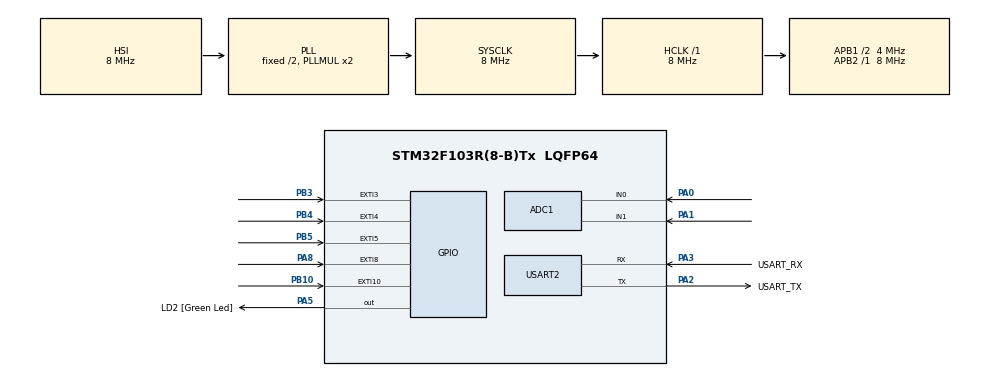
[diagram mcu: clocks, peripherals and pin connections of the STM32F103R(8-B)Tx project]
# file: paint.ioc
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ADC1.Channel-0\#ChannelRegularConversion=ADC_CHANNEL_0
ADC1.NbrOfConversionFlag=1
ADC1.Rank-0\#ChannelRegularConversion=1
ADC1.SamplingTime-0\#ChannelRegularConversion=ADC_SAMPLETIME_1CYCLE_5
ADC1.master=1
ADC2.Channel-0\#ChannelRegularConversion=ADC_CHANNEL_0
ADC2.NbrOfConversionFlag=1
ADC2.Rank-0\#ChannelRegularConversion=1
ADC2.SamplingTime-0\#ChannelRegularConversion=ADC_SAMPLETIME_1CYCLE_5
Mcu.Family=STM32F1
Mcu.Name=STM32F103R(8-B)Tx
Mcu.Package=LQFP64
NVIC.PriorityGroup=NVIC_PRIORITYGROUP_4
PA0-WKUP.Signal=SharedAnalog_PA0
PA1.Signal=SharedAnalog_PA1
PA13.GPIO_Label=TMS
PA13.Mode=Serial_Wire
PA13.Signal=SYS_JTMS-SWDIO
PA14.GPIO_Label=TCK
PA14.Mode=Serial_Wire
PA14.Signal=SYS_JTCK-SWCLK
PA2.GPIO_Label=USART_TX
PA2.GPIO_Mode=GPIO_MODE_AF_PP
PA2.GPIO_PuPd=GPIO_NOPULL
PA2.GPIO_Speed=GPIO_SPEED_FREQ_LOW
PA2.Mode=Asynchronous
PA2.Signal=USART2_TX
PA3.GPIO_Label=USART_RX
PA3.GPIO_Mode=GPIO_MODE_AF_PP
PA3.GPIO_PuPd=GPIO_NOPULL
PA3.GPIO_Speed=GPIO_SPEED_FREQ_LOW
PA3.Mode=Asynchronous
PA3.Signal=USART2_RX
PA5.GPIO_Label=LD2 [Green Led]
PA5.GPIO_ModeDefaultOutputPP=GPIO_MODE_OUTPUT_PP
PA5.GPIO_PuPd=GPIO_NOPULL
PA5.GPIO_Speed=GPIO_SPEED_FREQ_LOW
PA5.Signal=GPIO_Output
PA8.Signal=GPXTI8
PB10.Signal=GPXTI10
PB3.Signal=GPXTI3
PB4.Signal=GPXTI4
PB5.Signal=GPXTI5
PC14-OSC32_IN.Mode=LSE-External-Oscillator
PC14-OSC32_IN.Signal=RCC_OSC32_IN
PC15-OSC32_OUT.Mode=LSE-External-Oscillator
PC15-OSC32_OUT.Signal=RCC_OSC32_OUT
PD0-OSC_IN.Mode=HSE-External-Clock-Source
PD0-OSC_IN.Signal=RCC_OSC_IN
PD1-OSC_OUT.Mode=HSE-External-Clock-Source
PD1-OSC_OUT.Signal=RCC_OSC_OUT
ProjectManager.HeapSize=0x200
ProjectManager.StackSize=0x400
ProjectManager.TargetToolchain=MDK-ARM V5.32
RCC.AHBFreq_Value=8000000
RCC.APB1CLKDivider=RCC_HCLK_DIV2
RCC.APB1Freq_Value=4000000
RCC.APB1TimFreq_Value=8000000
RCC.APB2Freq_Value=8000000
RCC.APB2TimFreq_Value=8000000
RCC.HCLKFreq_Value=8000000
RCC.RTCClockSelection=RCC_RTCCLKSOURCE_LSE
RCC.SYSCLKFreq_VALUE=8000000
RCC.SYSCLKSource=RCC_SYSCLKSOURCE_PLLCLK
RCC.USBFreq_Value=8000000
SH.SharedAnalog_PA0.0=GPIO_Analog
SH.SharedAnalog_PA0.1=ADC1_IN0,IN0
SH.SharedAnalog_PA0.2=ADC2_IN0,IN0
SH.SharedAnalog_PA1.0=GPIO_Analog
SH.SharedAnalog_PA1.1=ADC1_IN1,IN1
SH.SharedAnalog_PA1.2=ADC2_IN1,IN1
USART2.VirtualMode=VM_ASYNC
board=NUCLEO-F103RB

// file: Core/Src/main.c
/* USER CODE BEGIN Header */
/**
  ******************************************************************************
  * @file           : main.c
  * @brief          : Main program body
  ******************************************************************************
  * @attention
  *
  * Copyright (c) 2025 STMicroelectronics.
  * All rights reserved.
  *
  * This software is licensed under terms that can be found in the LICENSE file
  * in the root directory of this software component.
  * If no LICENSE file comes with this software, it is provided AS-IS.
  *
  ******************************************************************************
  */
/* USER CODE END Header */
#include "main.h"

/* USER CODE BEGIN Includes */
#include <stdio.h>
#include <string.h>
/* USER CODE END Includes */

ADC_HandleTypeDef hadc1;
ADC_HandleTypeDef hadc2;

UART_HandleTypeDef huart2;

/* USER CODE BEGIN PV */
// Button state flags (set by interrupts, read in main loop)
volatile uint8_t buttonA_pressed = 0;
volatile uint8_t buttonB_pressed = 0;
volatile uint8_t buttonC_pressed = 0;
volatile uint8_t buttonD_pressed = 0;
volatile uint8_t buttonE_pressed = 0;
volatile uint8_t buttonF_pressed = 0;
volatile uint8_t joystickButton_pressed = 0;

/* USER CODE END PV */

void SystemClock_Config(void);
static void MX_GPIO_Init(void);
static void MX_USART2_UART_Init(void);
static void MX_ADC1_Init(void);
static void MX_ADC2_Init(void);
/* USER CODE BEGIN PFP */
uint16_t Read_ADC(ADC_HandleTypeDef* hadc);
void Send_UART_Data(uint16_t x, uint16_t y, uint8_t buttonE);
/* USER CODE END PFP */

int main(void)
{

  /* MCU Configuration--------------------------------------------------------*/

  /* Reset of all peripherals, Initializes the Flash interface and the Systick. */
  HAL_Init();

  /* Configure the system clock */
  SystemClock_Config();

  /* Initialize all configured peripherals */
  MX_GPIO_Init();
  MX_USART2_UART_Init();
  MX_ADC1_Init();
  MX_ADC2_Init();
  /* USER CODE BEGIN 2 */

  // Enable EXTI interrupts in NVIC
  // EXTI3 for PB3 (Button B)
  HAL_NVIC_SetPriority(EXTI3_IRQn, 0, 0);
  HAL_NVIC_EnableIRQ(EXTI3_IRQn);
  // EXTI4 for PB4 (Button C)
  HAL_NVIC_SetPriority(EXTI4_IRQn, 0, 0);
  HAL_NVIC_EnableIRQ(EXTI4_IRQn);
  // EXTI9_5 for PB5 (Button D), PA8 (Button F), PA9 (Joystick Button)
  HAL_NVIC_SetPriority(EXTI9_5_IRQn, 0, 0);
  HAL_NVIC_EnableIRQ(EXTI9_5_IRQn);
  // EXTI15_10 for PA10 (Button A), PB10 (Button E)
  HAL_NVIC_SetPriority(EXTI15_10_IRQn, 0, 0);
  HAL_NVIC_EnableIRQ(EXTI15_10_IRQn);

  /* USER CODE END 2 */

  /* Infinite loop */
  /* USER CODE BEGIN WHILE */
  uint32_t last_send_time = 0;

  while (1)
  {
    /* USER CODE END WHILE */

    /* USER CODE BEGIN 3 */
    // Read joystick position
    uint16_t joystick_x = Read_ADC(&hadc1);  // PA0 - X axis
    uint16_t joystick_y = Read_ADC(&hadc2);  // PA1 - Y axis

    // Send data via UART (every ~50ms to avoid flooding)
    uint32_t current_time = HAL_GetTick();
    if(current_time - last_send_time >= 50)
    {
      Send_UART_Data(joystick_x, joystick_y, 0);
      last_send_time = current_time;
    }

    // Handle button presses (send via UART immediately)
    if(buttonA_pressed)
    {
      char buf[32];
      sprintf(buf, "BTN:A\n");
      HAL_UART_Transmit(&huart2, (uint8_t*)buf, strlen(buf), 100);
      buttonA_pressed = 0;
    }
    if(buttonB_pressed)
    {
      char buf[32];
      sprintf(buf, "BTN:B\n");
      HAL_UART_Transmit(&huart2, (uint8_t*)buf, strlen(buf), 100);
      buttonB_pressed = 0;
    }
    if(buttonC_pressed)
    {
      char buf[32];
      sprintf(buf, "BTN:C\n");
      HAL_UART_Transmit(&huart2, (uint8_t*)buf, strlen(buf), 100);
      buttonC_pressed = 0;
    }
    if(buttonD_pressed)
    {
      char buf[32];
      sprintf(buf, "BTN:D\n");
      HAL_UART_Transmit(&huart2, (uint8_t*)buf, strlen(buf), 100);
      buttonD_pressed = 0;
    }
    if(buttonE_pressed)
    {
      char buf[32];
      sprintf(buf, "BTN:E\n");
      HAL_UART_Transmit(&huart2, (uint8_t*)buf, strlen(buf), 100);
      buttonE_pressed = 0;
    }
    if(buttonF_pressed)
    {
      char buf[32];
      sprintf(buf, "BTN:F\n");
      HAL_UART_Transmit(&huart2, (uint8_t*)buf, strlen(buf), 100);
      buttonF_pressed = 0;
    }
    if(joystickButton_pressed)
    {
      char buf[32];
      sprintf(buf, "BTN:JOY\n");
      HAL_UART_Transmit(&huart2, (uint8_t*)buf, strlen(buf), 100);
      joystickButton_pressed = 0;
    }

    HAL_Delay(10);
  }
  /* USER CODE END 3 */
}

void SystemClock_Config(void)
{
  RCC_OscInitTypeDef RCC_OscInitStruct = {0};
  RCC_ClkInitTypeDef RCC_ClkInitStruct = {0};
  RCC_PeriphCLKInitTypeDef PeriphClkInit = {0};

  /** Initializes the RCC Oscillators according to the specified parameters
  * in the RCC_OscInitTypeDef structure.
  */
  RCC_OscInitStruct.OscillatorType = RCC_OSCILLATORTYPE_HSI;
  RCC_OscInitStruct.HSIState = RCC_HSI_ON;
  RCC_OscInitStruct.HSICalibrationValue = RCC_HSICALIBRATION_DEFAULT;
  RCC_OscInitStruct.PLL.PLLState = RCC_PLL_ON;
  RCC_OscInitStruct.PLL.PLLSource = RCC_PLLSOURCE_HSI_DIV2;
  RCC_OscInitStruct.PLL.PLLMUL = RCC_PLL_MUL2;
  if (HAL_RCC_OscConfig(&RCC_OscInitStruct) != HAL_OK)
  {
    Error_Handler();
  }

  /** Initializes the CPU, AHB and APB buses clocks
  */
  RCC_ClkInitStruct.ClockType = RCC_CLOCKTYPE_HCLK|RCC_CLOCKTYPE_SYSCLK
                              |RCC_CLOCKTYPE_PCLK1|RCC_CLOCKTYPE_PCLK2;
  RCC_ClkInitStruct.SYSCLKSource = RCC_SYSCLKSOURCE_PLLCLK;
  RCC_ClkInitStruct.AHBCLKDivider = RCC_SYSCLK_DIV1;
  RCC_ClkInitStruct.APB1CLKDivider = RCC_HCLK_DIV2;
  RCC_ClkInitStruct.APB2CLKDivider = RCC_HCLK_DIV1;

  if (HAL_RCC_ClockConfig(&RCC_ClkInitStruct, FLASH_LATENCY_0) != HAL_OK)
  {
    Error_Handler();
  }
  PeriphClkInit.PeriphClockSelection = RCC_PERIPHCLK_ADC;
  PeriphClkInit.AdcClockSelection = RCC_ADCPCLK2_DIV2;
  if (HAL_RCCEx_PeriphCLKConfig(&PeriphClkInit) != HAL_OK)
  {
    Error_Handler();
  }
}

static void MX_ADC1_Init(void)
{

  ADC_ChannelConfTypeDef sConfig = {0};

  /** Common config
  */
  hadc1.Instance = ADC1;
  hadc1.Init.ScanConvMode = ADC_SCAN_DISABLE;
  hadc1.Init.ContinuousConvMode = DISABLE;
  hadc1.Init.DiscontinuousConvMode = DISABLE;
  hadc1.Init.ExternalTrigConv = ADC_SOFTWARE_START;
  hadc1.Init.DataAlign = ADC_DATAALIGN_RIGHT;
  hadc1.Init.NbrOfConversion = 1;
  if (HAL_ADC_Init(&hadc1) != HAL_OK)
  {
    Error_Handler();
  }

  /** Configure Regular Channel
  */
  sConfig.Channel = ADC_CHANNEL_0;
  sConfig.Rank = ADC_REGULAR_RANK_1;
  sConfig.SamplingTime = ADC_SAMPLETIME_1CYCLE_5;
  if (HAL_ADC_ConfigChannel(&hadc1, &sConfig) != HAL_OK)
  {
    Error_Handler();
  }

}

static void MX_ADC2_Init(void)
{

  ADC_ChannelConfTypeDef sConfig = {0};

  /** Common config
  */
  hadc2.Instance = ADC2;
  hadc2.Init.ScanConvMode = ADC_SCAN_DISABLE;
  hadc2.Init.ContinuousConvMode = DISABLE;
  hadc2.Init.DiscontinuousConvMode = DISABLE;
  hadc2.Init.ExternalTrigConv = ADC_SOFTWARE_START;
  hadc2.Init.DataAlign = ADC_DATAALIGN_RIGHT;
  hadc2.Init.NbrOfConversion = 1;
  if (HAL_ADC_Init(&hadc2) != HAL_OK)
  {
    Error_Handler();
  }

  /** Configure Regular Channel
  */
  sConfig.Channel = ADC_CHANNEL_1;
  sConfig.Rank = ADC_REGULAR_RANK_1;
  sConfig.SamplingTime = ADC_SAMPLETIME_1CYCLE_5;
  if (HAL_ADC_ConfigChannel(&hadc2, &sConfig) != HAL_OK)
  {
    Error_Handler();
  }

}

static void MX_USART2_UART_Init(void)
{

  huart2.Instance = USART2;
  huart2.Init.BaudRate = 115200;
  huart2.Init.WordLength = UART_WORDLENGTH_8B;
  huart2.Init.StopBits = UART_STOPBITS_1;
  huart2.Init.Parity = UART_PARITY_NONE;
  huart2.Init.Mode = UART_MODE_TX_RX;
  huart2.Init.HwFlowCtl = UART_HWCONTROL_NONE;
  huart2.Init.OverSampling = UART_OVERSAMPLING_16;
  if (HAL_UART_Init(&huart2) != HAL_OK)
  {
    Error_Handler();
  }

}

static void MX_GPIO_Init(void)
{
  GPIO_InitTypeDef GPIO_InitStruct = {0};

  /* GPIO Ports Clock Enable */
  __HAL_RCC_GPIOC_CLK_ENABLE();
  __HAL_RCC_GPIOD_CLK_ENABLE();
  __HAL_RCC_GPIOA_CLK_ENABLE();
  __HAL_RCC_GPIOB_CLK_ENABLE();

  /*Configure GPIO pin Output Level */
  HAL_GPIO_WritePin(LD2_GPIO_Port, LD2_Pin, GPIO_PIN_RESET);

  /*Configure GPIO pin : LD2_Pin */
  GPIO_InitStruct.Pin = LD2_Pin;
  GPIO_InitStruct.Mode = GPIO_MODE_OUTPUT_PP;
  GPIO_InitStruct.Pull = GPIO_NOPULL;
  GPIO_InitStruct.Speed = GPIO_SPEED_FREQ_LOW;
  HAL_GPIO_Init(LD2_GPIO_Port, &GPIO_InitStruct);

  /*Configure GPIO pins : PB3 PB4 PB5 - Buttons B, C, D (EXTI) */
  GPIO_InitStruct.Pin = GPIO_PIN_3|GPIO_PIN_4|GPIO_PIN_5;
  GPIO_InitStruct.Mode = GPIO_MODE_IT_RISING;
  GPIO_InitStruct.Pull = GPIO_NOPULL;
  HAL_GPIO_Init(GPIOB, &GPIO_InitStruct);

  /*Configure GPIO pins : PA8 PA9 PA10 - Button F, Joystick Button, Button A (EXTI) */
  GPIO_InitStruct.Pin = GPIO_PIN_8|GPIO_PIN_9|GPIO_PIN_10;
  GPIO_InitStruct.Mode = GPIO_MODE_IT_RISING;
  GPIO_InitStruct.Pull = GPIO_NOPULL;
  HAL_GPIO_Init(GPIOA, &GPIO_InitStruct);

  /*Configure GPIO pin : PB10 - Button E (EXTI) */
  GPIO_InitStruct.Pin = GPIO_PIN_10;
  GPIO_InitStruct.Mode = GPIO_MODE_IT_RISING;
  GPIO_InitStruct.Pull = GPIO_NOPULL;
  HAL_GPIO_Init(GPIOB, &GPIO_InitStruct);

}

/* USER CODE BEGIN 4 */

// Button callback functions (called from EXTI handlers)
void HAL_GPIO_EXTI_Callback(uint16_t GPIO_Pin)
{
  switch(GPIO_Pin)
  {
    case GPIO_PIN_8:  // Button F (PA8)
      buttonF_pressed = 1;
      break;
    case GPIO_PIN_9:  // Joystick Button (PA9)
      joystickButton_pressed = 1;
      break;
    case GPIO_PIN_10: // Button A (PA10) or Button E (PB10)
      // Need to check which port triggered
      if(HAL_GPIO_ReadPin(GPIOA, GPIO_PIN_10) == GPIO_PIN_SET)
        buttonA_pressed = 1;
      if(HAL_GPIO_ReadPin(GPIOB, GPIO_PIN_10) == GPIO_PIN_SET)
        buttonE_pressed = 1;
      break;
    case GPIO_PIN_3:  // Button B (PB3)
      buttonB_pressed = 1;
      break;
    case GPIO_PIN_4:  // Button C (PB4)
      buttonC_pressed = 1;
      break;
    case GPIO_PIN_5:  // Button D (PB5)
      buttonD_pressed = 1;
      break;
  }
}

// Function to read ADC value
uint16_t Read_ADC(ADC_HandleTypeDef* hadc)
{
  HAL_ADC_Start(hadc);
  HAL_ADC_PollForConversion(hadc, 100);
  uint16_t value = HAL_ADC_GetValue(hadc);
  HAL_ADC_Stop(hadc);
  return value;
}

// Function to send data via UART in format: "X:1234,Y:5678,B:0\n"
void Send_UART_Data(uint16_t x, uint16_t y, uint8_t buttonE)
{
  char uart_buffer[64];
  sprintf(uart_buffer, "X:%d,Y:%d,B:%d\n", x, y, buttonE);
  HAL_UART_Transmit(&huart2, (uint8_t*)uart_buffer, strlen(uart_buffer), 100);
}

/* USER CODE END 4 */

void Error_Handler(void)
{
  __disable_irq();
  while (1)
  {
  }
}
